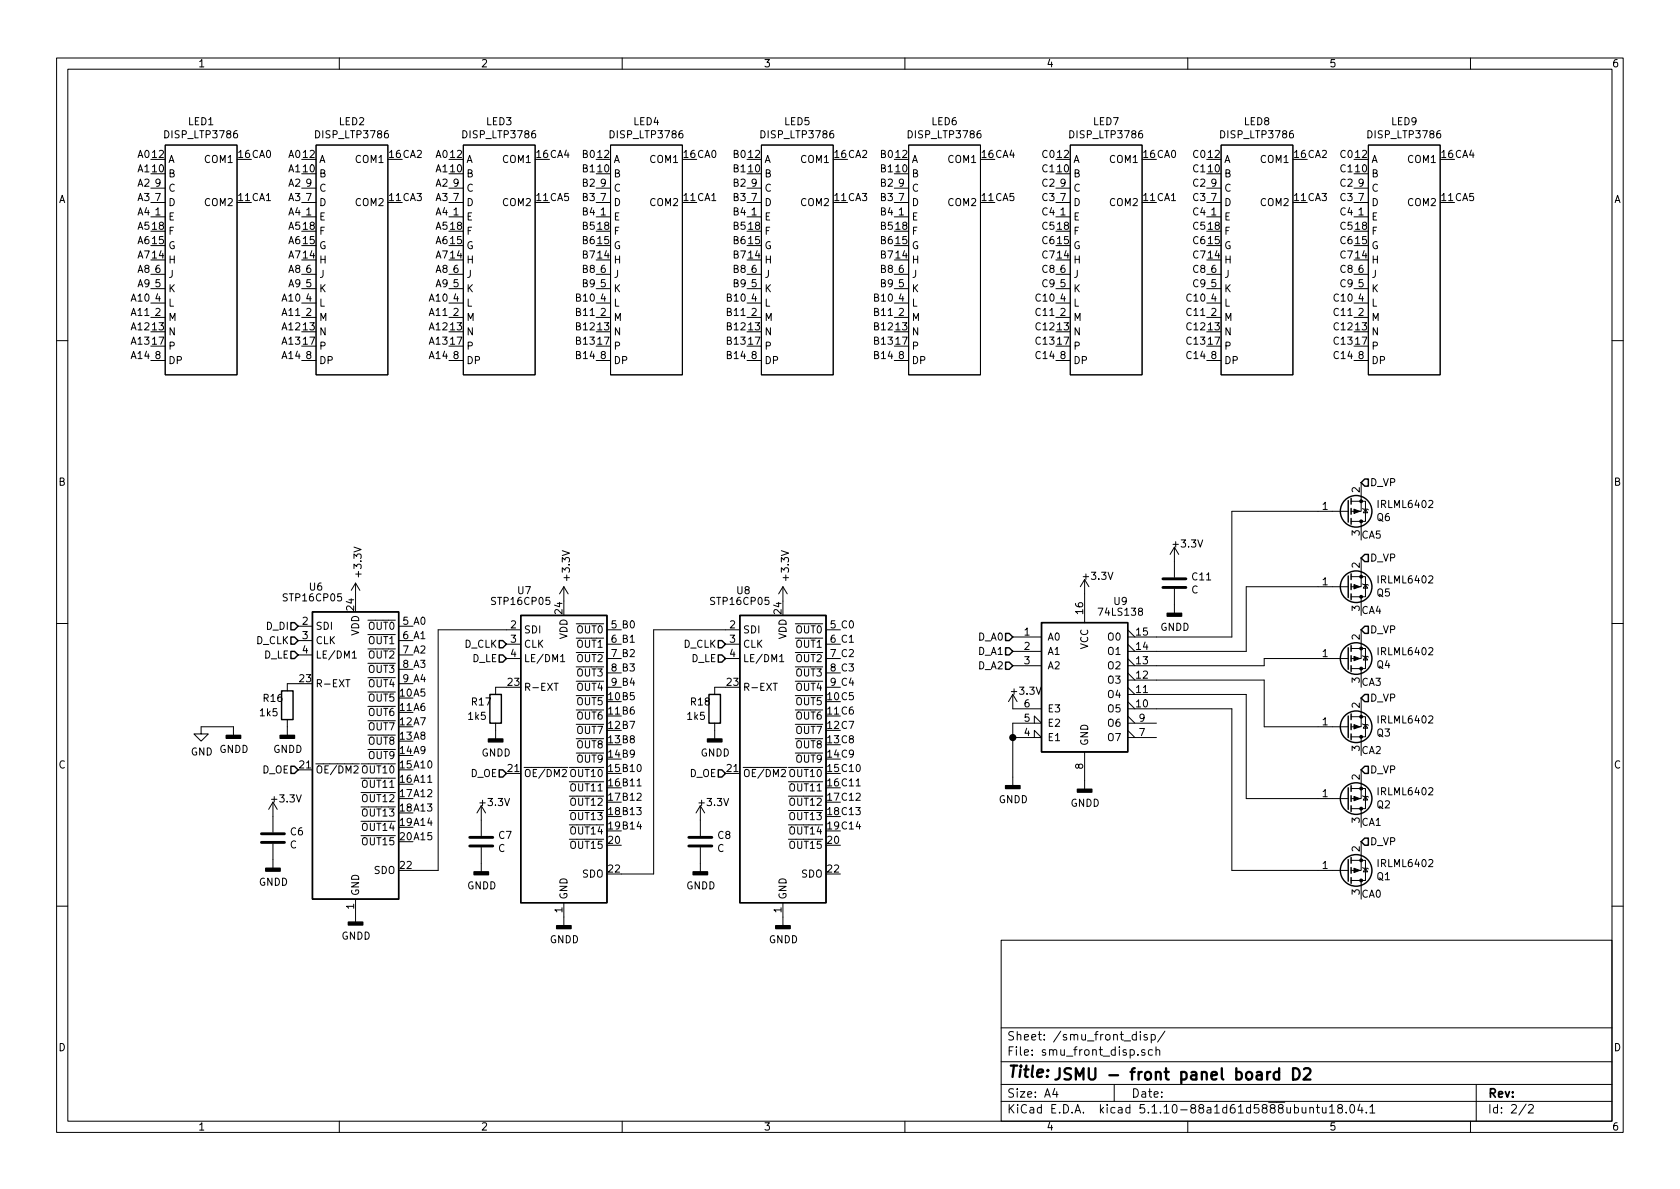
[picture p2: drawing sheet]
<svg xmlns="http://www.w3.org/2000/svg" width="297mm" height="210mm" viewBox="0 0 297 210" stroke-linecap="round" stroke-linejoin="round" font-family="sans-serif">
<defs><g id="words">
<text font-size="2.8" x="178" y="190.5">Title: JSMU - front panel board D2</text>
<g font-size="2.1">
<text x="178" y="184">Sheet: /smu_front_disp/</text>
<text x="178" y="186.7">File: smu_front_disp.sch</text>
<text x="178" y="196.9">KiCad E.D.A. kicad 5.1.10-88a1d61d5888ubuntu18.04.1</text>
<text x="178" y="194.1">Size: A4</text>
<text x="200" y="194.1">Date:</text>
<text x="263" y="194.1">Rev:</text>
<text x="263" y="196.9">Id: 2/2</text>
</g>
<g font-size="1.8">
<text x="35" y="11.9">1</text>
<text x="85" y="11.9">2</text>
<text x="135" y="11.9">3</text>
<text x="185" y="11.9">4</text>
<text x="235" y="11.9">5</text>
<text x="285" y="11.9">6</text>
<text x="33.3" y="22.1">LED1</text>
<text x="60" y="22.1">LED2</text>
<text x="86" y="22.1">LED3</text>
<text x="112" y="22.1">LED4</text>
<text x="138.7" y="22.1">LED5</text>
<text x="164.7" y="22.1">LED6</text>
<text x="193.3" y="22.1">LED7</text>
<text x="220" y="22.1">LED8</text>
<text x="246" y="22.1">LED9</text>
<text x="24.4" y="27.9">A0</text>
<text x="27" y="27.9">12</text>
<text x="29.4" y="24.5">DISP_LTP3786</text>
<text x="29.7" y="28.8">A</text>
<text x="36.3" y="28.8">COM1</text>
<text x="42.2" y="27.9">16CA0</text>
<text x="51.1" y="27.9">A0</text>
<text x="53.6" y="27.9">12</text>
<text x="56" y="24.5">DISP_LTP3786</text>
<text x="56.4" y="28.8">A</text>
<text x="63" y="28.8">COM1</text>
<text x="68.9" y="27.9">16CA2</text>
<text x="77.1" y="27.9">A0</text>
<text x="79.7" y="27.9">12</text>
<text x="82.1" y="24.5">DISP_LTP3786</text>
<text x="82.4" y="28.8">A</text>
<text x="89" y="28.8">COM1</text>
<text x="94.9" y="27.9">16CA4</text>
<text x="103.1" y="27.9">B0</text>
<text x="105.7" y="27.9">12</text>
<text x="108.1" y="24.5">DISP_LTP3786</text>
<text x="108.5" y="28.8">A</text>
<text x="115" y="28.8">COM1</text>
<text x="121" y="27.9">16CA0</text>
<text x="129.8" y="27.9">B0</text>
<text x="132.4" y="27.9">12</text>
<text x="134.8" y="24.5">DISP_LTP3786</text>
<text x="135.1" y="28.8">A</text>
<text x="141.7" y="28.8">COM1</text>
<text x="147.6" y="27.9">16CA2</text>
<text x="155.9" y="27.9">B0</text>
<text x="158.4" y="27.9">12</text>
<text x="160.8" y="24.5">DISP_LTP3786</text>
<text x="161.2" y="28.8">A</text>
<text x="167.7" y="28.8">COM1</text>
<text x="173.7" y="27.9">16CA4</text>
<text x="184.4" y="27.9">C0</text>
<text x="187" y="27.9">12</text>
<text x="189.4" y="24.5">DISP_LTP3786</text>
<text x="189.7" y="28.8">A</text>
<text x="196.3" y="28.8">COM1</text>
<text x="202.2" y="27.9">16CA0</text>
<text x="211.1" y="27.9">C0</text>
<text x="213.7" y="27.9">12</text>
<text x="216.1" y="24.5">DISP_LTP3786</text>
<text x="216.4" y="28.8">A</text>
<text x="223" y="28.8">COM1</text>
<text x="228.9" y="27.9">16CA2</text>
<text x="237.1" y="27.9">C0</text>
<text x="239.7" y="27.9">12</text>
<text x="242.1" y="24.5">DISP_LTP3786</text>
<text x="242.4" y="28.8">A</text>
<text x="249" y="28.8">COM1</text>
<text x="254.9" y="27.9">16CA4</text>
<text x="10.4" y="35.9">A</text>
<text x="24.4" y="30.5">A1</text>
<text x="24.4" y="33">A2</text>
<text x="24.4" y="35.6">A3</text>
<text x="27" y="30.5">10</text>
<text x="27.5" y="35.6">7</text>
<text x="27.5" y="33">9</text>
<text x="29.7" y="31.4">B</text>
<text x="29.7" y="33.9">C</text>
<text x="42.2" y="35.6">11CA1</text>
<text x="51.1" y="35.6">A3</text>
<text x="51.1" y="33">A2</text>
<text x="51.1" y="30.5">A1</text>
<text x="53.6" y="30.5">10</text>
<text x="54.1" y="35.6">7</text>
<text x="54.1" y="33">9</text>
<text x="56.4" y="31.4">B</text>
<text x="56.4" y="33.9">C</text>
<text x="68.9" y="35.6">11CA3</text>
<text x="77.1" y="35.6">A3</text>
<text x="77.1" y="33">A2</text>
<text x="77.1" y="30.5">A1</text>
<text x="79.7" y="30.5">10</text>
<text x="80.2" y="35.6">7</text>
<text x="80.2" y="33">9</text>
<text x="82.4" y="31.4">B</text>
<text x="82.4" y="33.9">C</text>
<text x="94.9" y="35.6">11CA5</text>
<text x="103.1" y="35.6">B3</text>
<text x="103.1" y="33">B2</text>
<text x="103.1" y="30.5">B1</text>
<text x="105.7" y="30.5">10</text>
<text x="106.2" y="35.6">7</text>
<text x="106.2" y="33">9</text>
<text x="108.5" y="31.4">B</text>
<text x="108.5" y="33.9">C</text>
<text x="121" y="35.6">11CA1</text>
<text x="129.8" y="35.6">B3</text>
<text x="129.8" y="33">B2</text>
<text x="129.8" y="30.5">B1</text>
<text x="132.4" y="30.5">10</text>
<text x="132.9" y="35.6">7</text>
<text x="132.9" y="33">9</text>
<text x="135.1" y="31.4">B</text>
<text x="135.1" y="33.9">C</text>
<text x="147.6" y="35.6">11CA3</text>
<text x="155.9" y="35.6">B3</text>
<text x="155.9" y="33">B2</text>
<text x="155.9" y="30.5">B1</text>
<text x="158.4" y="30.5">10</text>
<text x="158.9" y="35.6">7</text>
<text x="158.9" y="33">9</text>
<text x="161.2" y="31.4">B</text>
<text x="161.2" y="33.9">C</text>
<text x="173.7" y="35.6">11CA5</text>
<text x="184.4" y="35.6">C3</text>
<text x="184.4" y="33">C2</text>
<text x="184.4" y="30.5">C1</text>
<text x="187" y="30.5">10</text>
<text x="187.5" y="35.6">7</text>
<text x="187.5" y="33">9</text>
<text x="189.7" y="31.4">B</text>
<text x="189.7" y="33.9">C</text>
<text x="202.2" y="35.6">11CA1</text>
<text x="211.1" y="30.5">C1</text>
<text x="211.1" y="33">C2</text>
<text x="211.1" y="35.6">C3</text>
<text x="213.7" y="30.5">10</text>
<text x="214.1" y="35.6">7</text>
<text x="214.1" y="33">9</text>
<text x="216.4" y="31.4">B</text>
<text x="216.4" y="33.9">C</text>
<text x="228.9" y="35.6">11CA3</text>
<text x="237.1" y="35.6">C3</text>
<text x="237.1" y="33">C2</text>
<text x="237.1" y="30.5">C1</text>
<text x="239.7" y="30.5">10</text>
<text x="240.2" y="35.6">7</text>
<text x="240.2" y="33">9</text>
<text x="242.4" y="31.4">B</text>
<text x="242.4" y="33.9">C</text>
<text x="254.9" y="35.6">11CA5</text>
<text x="285.4" y="35.9">A</text>
<text x="24.4" y="40.6">A5</text>
<text x="24.4" y="38.1">A4</text>
<text x="27" y="40.6">18</text>
<text x="27.5" y="38.1">1</text>
<text x="29.7" y="39">E</text>
<text x="29.7" y="41.5">F</text>
<text x="29.7" y="36.4">D</text>
<text x="36.3" y="36.4">COM2</text>
<text x="51.1" y="40.6">A5</text>
<text x="51.1" y="38.1">A4</text>
<text x="53.6" y="40.6">18</text>
<text x="54.1" y="38.1">1</text>
<text x="56.4" y="39">E</text>
<text x="56.4" y="41.5">F</text>
<text x="56.4" y="36.4">D</text>
<text x="63" y="36.4">COM2</text>
<text x="77.1" y="40.6">A5</text>
<text x="77.1" y="38.1">A4</text>
<text x="79.7" y="40.6">18</text>
<text x="80.2" y="38.1">1</text>
<text x="82.4" y="39">E</text>
<text x="82.4" y="41.5">F</text>
<text x="82.4" y="36.4">D</text>
<text x="89" y="36.4">COM2</text>
<text x="103.1" y="40.6">B5</text>
<text x="103.1" y="38.1">B4</text>
<text x="105.7" y="40.6">18</text>
<text x="106.2" y="38.1">1</text>
<text x="108.5" y="39">E</text>
<text x="108.5" y="41.5">F</text>
<text x="108.5" y="36.4">D</text>
<text x="115" y="36.4">COM2</text>
<text x="129.8" y="40.6">B5</text>
<text x="129.8" y="38.1">B4</text>
<text x="132.4" y="40.6">18</text>
<text x="132.9" y="38.1">1</text>
<text x="135.1" y="39">E</text>
<text x="135.1" y="41.5">F</text>
<text x="135.1" y="36.4">D</text>
<text x="141.7" y="36.4">COM2</text>
<text x="155.9" y="38.1">B4</text>
<text x="155.9" y="40.6">B5</text>
<text x="158.4" y="40.6">18</text>
<text x="158.9" y="38.1">1</text>
<text x="161.2" y="39">E</text>
<text x="161.2" y="41.5">F</text>
<text x="161.2" y="36.4">D</text>
<text x="167.7" y="36.4">COM2</text>
<text x="184.4" y="40.6">C5</text>
<text x="184.4" y="38.1">C4</text>
<text x="187" y="40.6">18</text>
<text x="187.5" y="38.1">1</text>
<text x="189.7" y="39">E</text>
<text x="189.7" y="41.5">F</text>
<text x="189.7" y="36.4">D</text>
<text x="196.3" y="36.4">COM2</text>
<text x="211.1" y="40.6">C5</text>
<text x="211.1" y="38.1">C4</text>
<text x="213.7" y="40.6">18</text>
<text x="214.1" y="38.1">1</text>
<text x="216.4" y="39">E</text>
<text x="216.4" y="41.5">F</text>
<text x="216.4" y="36.4">D</text>
<text x="223" y="36.4">COM2</text>
<text x="237.1" y="40.6">C5</text>
<text x="237.1" y="38.1">C4</text>
<text x="239.7" y="40.6">18</text>
<text x="240.2" y="38.1">1</text>
<text x="242.4" y="39">E</text>
<text x="242.4" y="41.5">F</text>
<text x="242.4" y="36.4">D</text>
<text x="249" y="36.4">COM2</text>
<text x="24.4" y="45.7">A7</text>
<text x="24.4" y="43.2">A6</text>
<text x="27" y="45.7">14</text>
<text x="27" y="43.2">15</text>
<text x="29.7" y="46.6">H</text>
<text x="29.7" y="44.1">G</text>
<text x="51.1" y="45.7">A7</text>
<text x="51.1" y="43.2">A6</text>
<text x="53.6" y="45.7">14</text>
<text x="53.6" y="43.2">15</text>
<text x="56.4" y="46.6">H</text>
<text x="56.4" y="44.1">G</text>
<text x="77.1" y="45.7">A7</text>
<text x="77.1" y="43.2">A6</text>
<text x="79.7" y="45.7">14</text>
<text x="79.7" y="43.2">15</text>
<text x="82.4" y="46.6">H</text>
<text x="82.4" y="44.1">G</text>
<text x="103.1" y="45.7">B7</text>
<text x="103.1" y="43.2">B6</text>
<text x="105.7" y="45.7">14</text>
<text x="105.7" y="43.2">15</text>
<text x="108.5" y="46.6">H</text>
<text x="108.5" y="44.1">G</text>
<text x="129.8" y="45.7">B7</text>
<text x="129.8" y="43.2">B6</text>
<text x="132.4" y="45.7">14</text>
<text x="132.4" y="43.2">15</text>
<text x="135.1" y="46.6">H</text>
<text x="135.1" y="44.1">G</text>
<text x="155.9" y="45.7">B7</text>
<text x="155.9" y="43.2">B6</text>
<text x="158.4" y="45.7">14</text>
<text x="158.4" y="43.2">15</text>
<text x="161.2" y="46.6">H</text>
<text x="161.2" y="44.1">G</text>
<text x="184.4" y="45.7">C7</text>
<text x="184.4" y="43.2">C6</text>
<text x="187" y="45.7">14</text>
<text x="187" y="43.2">15</text>
<text x="189.7" y="46.6">H</text>
<text x="189.7" y="44.1">G</text>
<text x="211.1" y="43.2">C6</text>
<text x="211.1" y="45.7">C7</text>
<text x="213.7" y="45.7">14</text>
<text x="213.7" y="43.2">15</text>
<text x="216.4" y="46.6">H</text>
<text x="216.4" y="44.1">G</text>
<text x="237.1" y="45.7">C7</text>
<text x="237.1" y="43.2">C6</text>
<text x="239.7" y="45.7">14</text>
<text x="239.7" y="43.2">15</text>
<text x="242.4" y="46.6">H</text>
<text x="242.4" y="44.1">G</text>
<text x="23.4" y="53.3">A10</text>
<text x="24.4" y="50.8">A9</text>
<text x="24.4" y="48.3">A8</text>
<text x="27.5" y="53.3">4</text>
<text x="27.5" y="50.8">5</text>
<text x="27.5" y="48.3">6</text>
<text x="29.7" y="51.7">K</text>
<text x="29.7" y="49.1">J</text>
<text x="50.1" y="53.3">A10</text>
<text x="51.1" y="50.8">A9</text>
<text x="51.1" y="48.3">A8</text>
<text x="54.1" y="53.3">4</text>
<text x="54.1" y="50.8">5</text>
<text x="54.1" y="48.3">6</text>
<text x="56.4" y="51.7">K</text>
<text x="56.4" y="49.1">J</text>
<text x="76.1" y="53.3">A10</text>
<text x="77.1" y="48.3">A8</text>
<text x="77.1" y="50.8">A9</text>
<text x="80.2" y="53.3">4</text>
<text x="80.2" y="50.8">5</text>
<text x="80.2" y="48.3">6</text>
<text x="82.4" y="51.7">K</text>
<text x="82.4" y="49.1">J</text>
<text x="102.2" y="53.3">B10</text>
<text x="103.1" y="50.8">B9</text>
<text x="103.1" y="48.3">B8</text>
<text x="106.2" y="53.3">4</text>
<text x="106.2" y="50.8">5</text>
<text x="106.2" y="48.3">6</text>
<text x="108.5" y="51.7">K</text>
<text x="108.5" y="49.1">J</text>
<text x="128.8" y="53.3">B10</text>
<text x="129.8" y="50.8">B9</text>
<text x="129.8" y="48.3">B8</text>
<text x="132.9" y="53.3">4</text>
<text x="132.9" y="50.8">5</text>
<text x="132.9" y="48.3">6</text>
<text x="135.1" y="51.7">K</text>
<text x="135.1" y="49.1">J</text>
<text x="154.9" y="53.3">B10</text>
<text x="155.9" y="50.8">B9</text>
<text x="155.9" y="48.3">B8</text>
<text x="158.9" y="53.3">4</text>
<text x="158.9" y="50.8">5</text>
<text x="158.9" y="48.3">6</text>
<text x="161.2" y="51.7">K</text>
<text x="161.2" y="49.1">J</text>
<text x="183.4" y="53.3">C10</text>
<text x="184.4" y="48.3">C8</text>
<text x="184.4" y="50.8">C9</text>
<text x="187.5" y="53.3">4</text>
<text x="187.5" y="50.8">5</text>
<text x="187.5" y="48.3">6</text>
<text x="189.7" y="51.7">K</text>
<text x="189.7" y="49.1">J</text>
<text x="210.1" y="53.3">C10</text>
<text x="211.1" y="50.8">C9</text>
<text x="211.1" y="48.3">C8</text>
<text x="214.1" y="53.3">4</text>
<text x="214.1" y="50.8">5</text>
<text x="214.1" y="48.3">6</text>
<text x="216.4" y="51.7">K</text>
<text x="216.4" y="49.1">J</text>
<text x="236.1" y="53.3">C10</text>
<text x="237.1" y="50.8">C9</text>
<text x="237.1" y="48.3">C8</text>
<text x="240.2" y="53.3">4</text>
<text x="240.2" y="50.8">5</text>
<text x="240.2" y="48.3">6</text>
<text x="242.4" y="51.7">K</text>
<text x="242.4" y="49.1">J</text>
<text x="23.4" y="55.9">A11</text>
<text x="23.4" y="58.4">A12</text>
<text x="27" y="58.4">13</text>
<text x="27.5" y="55.9">2</text>
<text x="29.7" y="59.3">N</text>
<text x="29.7" y="56.8">M</text>
<text x="29.7" y="54.2">L</text>
<text x="50.1" y="58.4">A12</text>
<text x="50.1" y="55.9">A11</text>
<text x="53.6" y="58.4">13</text>
<text x="54.1" y="55.9">2</text>
<text x="56.4" y="59.3">N</text>
<text x="56.4" y="56.8">M</text>
<text x="56.4" y="54.2">L</text>
<text x="76.1" y="58.4">A12</text>
<text x="76.1" y="55.9">A11</text>
<text x="79.7" y="58.4">13</text>
<text x="80.2" y="55.9">2</text>
<text x="82.4" y="59.3">N</text>
<text x="82.4" y="56.8">M</text>
<text x="82.4" y="54.2">L</text>
<text x="102.2" y="58.4">B12</text>
<text x="102.2" y="55.9">B11</text>
<text x="105.7" y="58.4">13</text>
<text x="106.2" y="55.9">2</text>
<text x="108.5" y="59.3">N</text>
<text x="108.5" y="56.8">M</text>
<text x="108.5" y="54.2">L</text>
<text x="128.8" y="58.4">B12</text>
<text x="128.8" y="55.9">B11</text>
<text x="132.4" y="58.4">13</text>
<text x="132.9" y="55.9">2</text>
<text x="135.1" y="59.3">N</text>
<text x="135.1" y="56.8">M</text>
<text x="135.1" y="54.2">L</text>
<text x="154.9" y="58.4">B12</text>
<text x="154.9" y="55.9">B11</text>
<text x="158.4" y="58.4">13</text>
<text x="158.9" y="55.9">2</text>
<text x="161.2" y="59.3">N</text>
<text x="161.2" y="56.8">M</text>
<text x="161.2" y="54.2">L</text>
<text x="183.4" y="55.9">C11</text>
<text x="183.4" y="58.4">C12</text>
<text x="187" y="58.4">13</text>
<text x="187.5" y="55.9">2</text>
<text x="189.7" y="59.3">N</text>
<text x="189.7" y="56.8">M</text>
<text x="189.7" y="54.2">L</text>
<text x="210.1" y="58.4">C12</text>
<text x="210.1" y="55.9">C11</text>
<text x="213.7" y="58.4">13</text>
<text x="214.1" y="55.9">2</text>
<text x="216.4" y="59.3">N</text>
<text x="216.4" y="56.8">M</text>
<text x="216.4" y="54.2">L</text>
<text x="236.1" y="58.4">C12</text>
<text x="236.1" y="55.9">C11</text>
<text x="239.7" y="58.4">13</text>
<text x="240.2" y="55.9">2</text>
<text x="242.4" y="59.3">N</text>
<text x="242.4" y="56.8">M</text>
<text x="242.4" y="54.2">L</text>
<text x="23.4" y="63.5">A14</text>
<text x="23.4" y="61">A13</text>
<text x="27" y="61">17</text>
<text x="27.5" y="63.5">8</text>
<text x="29.7" y="61.8">P</text>
<text x="29.7" y="64.4">DP</text>
<text x="50.1" y="63.5">A14</text>
<text x="50.1" y="61">A13</text>
<text x="53.6" y="61">17</text>
<text x="54.1" y="63.5">8</text>
<text x="56.4" y="61.8">P</text>
<text x="56.4" y="64.4">DP</text>
<text x="76.1" y="63.5">A14</text>
<text x="76.1" y="61">A13</text>
<text x="79.7" y="61">17</text>
<text x="80.2" y="63.5">8</text>
<text x="82.4" y="61.8">P</text>
<text x="82.4" y="64.4">DP</text>
<text x="102.2" y="63.5">B14</text>
<text x="102.2" y="61">B13</text>
<text x="105.7" y="61">17</text>
<text x="106.2" y="63.5">8</text>
<text x="108.5" y="61.8">P</text>
<text x="108.5" y="64.4">DP</text>
<text x="128.8" y="63.5">B14</text>
<text x="128.8" y="61">B13</text>
<text x="132.4" y="61">17</text>
<text x="132.9" y="63.5">8</text>
<text x="135.1" y="61.8">P</text>
<text x="135.1" y="64.4">DP</text>
<text x="154.9" y="61">B13</text>
<text x="154.9" y="63.5">B14</text>
<text x="158.4" y="61">17</text>
<text x="158.9" y="63.5">8</text>
<text x="161.2" y="61.8">P</text>
<text x="161.2" y="64.4">DP</text>
<text x="183.4" y="61">C13</text>
<text x="183.4" y="63.5">C14</text>
<text x="187" y="61">17</text>
<text x="187.5" y="63.5">8</text>
<text x="189.7" y="61.8">P</text>
<text x="189.7" y="64.4">DP</text>
<text x="210.1" y="63.5">C14</text>
<text x="210.1" y="61">C13</text>
<text x="213.7" y="61">17</text>
<text x="214.1" y="63.5">8</text>
<text x="216.4" y="61.8">P</text>
<text x="216.4" y="64.4">DP</text>
<text x="236.1" y="63.5">C14</text>
<text x="236.1" y="61">C13</text>
<text x="239.7" y="61">17</text>
<text x="240.2" y="63.5">8</text>
<text x="242.4" y="61.8">P</text>
<text x="242.4" y="64.4">DP</text>
<text x="10.4" y="85.9">B</text>
<text x="240.4" y="87.1" transform="rotate(-90 240.4 87.1)">2</text>
<text x="242.2" y="86">D_VP</text>
<text x="243.8" y="89.8">IRLML6402</text>
<text x="285.4" y="85.9">B</text>
<text x="233.8" y="90.2">1</text>
<text x="240.4" y="94.7" transform="rotate(-90 240.4 94.7)">3</text>
<text x="240.7" y="95.2">CA5</text>
<text x="243.5" y="92.1">Q6</text>
<text x="63.9" y="101.8" transform="rotate(-90 63.9 101.8)">+3.3V</text>
<text x="207.6" y="96.8">+3.3V</text>
<text x="240.4" y="100.4" transform="rotate(-90 240.4 100.4)">2</text>
<text x="242.2" y="99.3">D_VP</text>
<text x="50.3" y="106.3">STP16CP05</text>
<text x="54.8" y="104.4">U6</text>
<text x="62.6" y="107.9" transform="rotate(-90 62.6 107.9)">24</text>
<text x="87.2" y="107">STP16CP05</text>
<text x="91.6" y="105.1">U7</text>
<text x="100.8" y="102.5" transform="rotate(-90 100.8 102.5)">+3.3V</text>
<text x="125.9" y="107">STP16CP05</text>
<text x="130.3" y="105.1">U8</text>
<text x="139.5" y="102.5" transform="rotate(-90 139.5 102.5)">+3.3V</text>
<text x="191.7" y="102.5">+3.3V</text>
<text x="197" y="107">U9</text>
<text x="210.6" y="104.9">C</text>
<text x="210.8" y="102.6">C11</text>
<text x="233.8" y="103.5">1</text>
<text x="243.5" y="105.5">Q5</text>
<text x="243.8" y="103.2">IRLML6402</text>
<text x="45.3" y="113.9">D_CLK</text>
<text x="47.1" y="111.4">D_DI</text>
<text x="53.5" y="110.5">2</text>
<text x="53.5" y="113">3</text>
<text x="55.8" y="111.4">SDI</text>
<text x="55.8" y="113.9">CLK</text>
<text x="63.5" y="112.4" transform="rotate(-90 63.5 112.4)">VDD</text>
<text x="65.3" y="111.4">OUT0</text>
<text x="65.3" y="113.9">OUT1</text>
<text x="71.3" y="110.5">5 A0</text>
<text x="71.3" y="113">6 A1</text>
<text x="90.3" y="111.1">2</text>
<text x="90.3" y="113.7">3</text>
<text x="92.6" y="112">SDI</text>
<text x="99.4" y="108.5" transform="rotate(-90 99.4 108.5)">24</text>
<text x="100.3" y="113.1" transform="rotate(-90 100.3 113.1)">VDD</text>
<text x="102.1" y="112">OUT0</text>
<text x="108.1" y="111.1">5 B0</text>
<text x="108.1" y="113.7">6 B1</text>
<text x="129.1" y="111.1">2</text>
<text x="129.1" y="113.7">3</text>
<text x="131.3" y="112">SDI</text>
<text x="138.2" y="108.5" transform="rotate(-90 138.2 108.5)">24</text>
<text x="139.1" y="113.1" transform="rotate(-90 139.1 113.1)">VDD</text>
<text x="140.8" y="112">OUT0</text>
<text x="146.8" y="111.1">5 C0</text>
<text x="146.8" y="113.7">6 C1</text>
<text x="173" y="113.3">D_A0</text>
<text x="181.1" y="112.4">1</text>
<text x="185.2" y="113.3">A0</text>
<text x="191.5" y="108.5" transform="rotate(-90 191.5 108.5)">16</text>
<text x="194.5" y="108.9">74LS138</text>
<text x="196" y="113.3">O0</text>
<text x="201" y="112.4">15</text>
<text x="205.2" y="111.6">GNDD</text>
<text x="240.4" y="113.1" transform="rotate(-90 240.4 113.1)">2</text>
<text x="240.4" y="108" transform="rotate(-90 240.4 108)">3</text>
<text x="240.7" y="108.6">CA4</text>
<text x="242.2" y="112">D_VP</text>
<text x="46.7" y="116.5">D_LE</text>
<text x="53.5" y="115.6">4</text>
<text x="55.8" y="116.5">LE/DM1</text>
<text x="65.3" y="116.5">OUT2</text>
<text x="65.3" y="119">OUT3</text>
<text x="71.3" y="115.6">7 A2</text>
<text x="71.3" y="118.1">8 A3</text>
<text x="82.1" y="114.5">D_CLK</text>
<text x="83.5" y="117.1">D_LE</text>
<text x="90.3" y="116.2">4</text>
<text x="92.6" y="114.5">CLK</text>
<text x="92.6" y="117.1">LE/DM1</text>
<text x="102.1" y="114.5">OUT1</text>
<text x="102.1" y="117.1">OUT2</text>
<text x="102.1" y="119.6">OUT3</text>
<text x="108.1" y="116.2">7 B2</text>
<text x="108.1" y="118.7">8 B3</text>
<text x="120.9" y="114.5">D_CLK</text>
<text x="122.2" y="117.1">D_LE</text>
<text x="129.1" y="116.2">4</text>
<text x="131.3" y="114.5">CLK</text>
<text x="131.3" y="117.1">LE/DM1</text>
<text x="140.8" y="114.5">OUT1</text>
<text x="140.8" y="117.1">OUT2</text>
<text x="140.8" y="119.6">OUT3</text>
<text x="146.8" y="116.2">7 C2</text>
<text x="146.8" y="118.7">8 C3</text>
<text x="173" y="115.8">D_A1</text>
<text x="173" y="118.4">D_A2</text>
<text x="181.1" y="114.9">2</text>
<text x="181.1" y="117.5">3</text>
<text x="185.2" y="115.8">A1</text>
<text x="185.2" y="118.4">A2</text>
<text x="192.4" y="114.9" transform="rotate(-90 192.4 114.9)">VCC</text>
<text x="196" y="118.4">O2</text>
<text x="196" y="115.8">O1</text>
<text x="201" y="117.5">13</text>
<text x="201" y="114.9">14</text>
<text x="233.8" y="116.2">1</text>
<text x="243.5" y="118.2">Q4</text>
<text x="243.8" y="115.9">IRLML6402</text>
<text x="46.6" y="124.1">R16</text>
<text x="53" y="120.6">23</text>
<text x="55.8" y="121.5">R-EXT</text>
<text x="65.3" y="124.1">OUT5</text>
<text x="65.3" y="121.5">OUT4</text>
<text x="70.8" y="123.2">10A5</text>
<text x="70.8" y="125.7">11A6</text>
<text x="71.3" y="120.6">9 A4</text>
<text x="83.5" y="124.8">R17</text>
<text x="89.8" y="121.3">23</text>
<text x="92.6" y="122.2">R-EXT</text>
<text x="102.1" y="124.7">OUT5</text>
<text x="102.1" y="122.2">OUT4</text>
<text x="107.6" y="123.8">10B5</text>
<text x="108.1" y="121.3">9 B4</text>
<text x="122.2" y="124.8">R18</text>
<text x="128.6" y="121.3">23</text>
<text x="131.3" y="122.2">R-EXT</text>
<text x="140.8" y="124.7">OUT5</text>
<text x="140.8" y="122.2">OUT4</text>
<text x="146.4" y="123.8">10C5</text>
<text x="146.8" y="121.3">9 C4</text>
<text x="179" y="122.9">+3.3V</text>
<text x="181.1" y="125.1">6</text>
<text x="185.2" y="126">E3</text>
<text x="196" y="126">O5</text>
<text x="196" y="123.4">O4</text>
<text x="196" y="120.9">O3</text>
<text x="201" y="125.1">10</text>
<text x="201" y="122.5">11</text>
<text x="201" y="120">12</text>
<text x="240.4" y="125.2" transform="rotate(-90 240.4 125.2)">2</text>
<text x="240.4" y="120.7" transform="rotate(-90 240.4 120.7)">3</text>
<text x="240.7" y="121.3">CA3</text>
<text x="242.2" y="124.1">D_VP</text>
<text x="46.1" y="126.7">1k5</text>
<text x="65.3" y="126.6">OUT6</text>
<text x="65.3" y="129.2">OUT7</text>
<text x="65.3" y="131.7">OUT8</text>
<text x="70.8" y="128.3">12A7</text>
<text x="70.8" y="130.8">13A8</text>
<text x="82.9" y="127.3">1k5</text>
<text x="102.1" y="127.2">OUT6</text>
<text x="102.1" y="129.8">OUT7</text>
<text x="107.6" y="126.4">11B6</text>
<text x="107.6" y="128.9">12B7</text>
<text x="107.6" y="131.4">13B8</text>
<text x="121.6" y="127.3">1k5</text>
<text x="140.8" y="127.2">OUT6</text>
<text x="140.8" y="129.8">OUT7</text>
<text x="146.4" y="126.4">11C6</text>
<text x="146.4" y="128.9">12C7</text>
<text x="146.4" y="131.4">13C8</text>
<text x="181.1" y="130.2">4</text>
<text x="181.1" y="127.6">5</text>
<text x="185.2" y="131.1">E1</text>
<text x="185.2" y="128.5">E2</text>
<text x="192.4" y="131.9" transform="rotate(-90 192.4 131.9)">GND</text>
<text x="196" y="131.1">O7</text>
<text x="196" y="128.5">O6</text>
<text x="201.4" y="130.2">7</text>
<text x="201.4" y="127.6">9</text>
<text x="233.8" y="128.3">1</text>
<text x="243.5" y="130.2">Q3</text>
<text x="243.8" y="127.9">IRLML6402</text>
<text x="10.4" y="135.9">C</text>
<text x="33.7" y="133.6">GND</text>
<text x="38.8" y="133.1">GNDD</text>
<text x="46.4" y="136.8">D_OE</text>
<text x="48.3" y="133.1">GNDD</text>
<text x="53" y="135.9">21</text>
<text x="55.8" y="136.8">OE/DM2</text>
<text x="64.3" y="136.8">OUT10</text>
<text x="65.3" y="134.2">OUT9</text>
<text x="70.8" y="133.3">14A9</text>
<text x="70.8" y="135.9">15A10</text>
<text x="83.2" y="137.4">D_OE</text>
<text x="85.1" y="133.8">GNDD</text>
<text x="89.8" y="136.5">21</text>
<text x="92.6" y="137.4">OE/DM2</text>
<text x="101.1" y="137.4">OUT10</text>
<text x="102.1" y="132.3">OUT8</text>
<text x="102.1" y="134.9">OUT9</text>
<text x="107.6" y="134">14B9</text>
<text x="107.6" y="136.5">15B10</text>
<text x="121.9" y="137.4">D_OE</text>
<text x="123.9" y="133.8">GNDD</text>
<text x="128.6" y="136.5">21</text>
<text x="131.3" y="137.4">OE/DM2</text>
<text x="139.9" y="137.4">OUT10</text>
<text x="140.8" y="132.3">OUT8</text>
<text x="140.8" y="134.9">OUT9</text>
<text x="146.4" y="134">14C9</text>
<text x="146.4" y="136.5">15C10</text>
<text x="191.5" y="136" transform="rotate(-90 191.5 136)">8</text>
<text x="240.4" y="137.9" transform="rotate(-90 240.4 137.9)">2</text>
<text x="240.4" y="132.8" transform="rotate(-90 240.4 132.8)">3</text>
<text x="240.7" y="133.3">CA2</text>
<text x="242.2" y="136.8">D_VP</text>
<text x="285.4" y="135.9">C</text>
<text x="48.2" y="141.9">+3.3V</text>
<text x="64.3" y="139.3">OUT11</text>
<text x="64.3" y="141.9">OUT12</text>
<text x="70.8" y="138.4">16A11</text>
<text x="70.8" y="141">17A12</text>
<text x="70.8" y="143.5">18A13</text>
<text x="85" y="142.5">+3.3V</text>
<text x="101.1" y="139.9">OUT11</text>
<text x="101.1" y="142.5">OUT12</text>
<text x="107.6" y="139.1">16B11</text>
<text x="107.6" y="141.6">17B12</text>
<text x="123.8" y="142.5">+3.3V</text>
<text x="139.9" y="139.9">OUT11</text>
<text x="139.9" y="142.5">OUT12</text>
<text x="146.4" y="139.1">16C11</text>
<text x="146.4" y="141.6">17C12</text>
<text x="176.6" y="142">GNDD</text>
<text x="189.3" y="142.7">GNDD</text>
<text x="233.8" y="141">1</text>
<text x="243.5" y="142.9">Q2</text>
<text x="243.8" y="140.6">IRLML6402</text>
<text x="51.4" y="147.7">C6</text>
<text x="64.3" y="144.4">OUT13</text>
<text x="64.3" y="146.9">OUT14</text>
<text x="64.3" y="149.5">OUT15</text>
<text x="70.8" y="146">19A14</text>
<text x="70.8" y="148.6">20A15</text>
<text x="88.2" y="148.4">C7</text>
<text x="101.1" y="145">OUT13</text>
<text x="101.1" y="147.6">OUT14</text>
<text x="107.6" y="144.1">18B13</text>
<text x="107.6" y="146.7">19B14</text>
<text x="107.6" y="149.2">20</text>
<text x="126.9" y="148.4">C8</text>
<text x="139.9" y="145">OUT13</text>
<text x="139.9" y="147.6">OUT14</text>
<text x="146.4" y="144.1">18C13</text>
<text x="146.4" y="146.7">19C14</text>
<text x="146.4" y="149.2">20</text>
<text x="240.4" y="145.5" transform="rotate(-90 240.4 145.5)">3</text>
<text x="240.7" y="146">CA1</text>
<text x="242.2" y="149.5">D_VP</text>
<text x="51.3" y="150">C</text>
<text x="66.1" y="154.6">SDO</text>
<text x="70.8" y="153.7">22</text>
<text x="88.1" y="150.7">C</text>
<text x="101.1" y="150.1">OUT15</text>
<text x="103" y="155.2">SDO</text>
<text x="107.6" y="154.3">22</text>
<text x="126.8" y="150.7">C</text>
<text x="139.9" y="150.1">OUT15</text>
<text x="141.7" y="155.2">SDO</text>
<text x="146.4" y="154.3">22</text>
<text x="233.8" y="153.7">1</text>
<text x="240.4" y="150.6" transform="rotate(-90 240.4 150.6)">2</text>
<text x="243.5" y="155.6">Q1</text>
<text x="243.8" y="153.3">IRLML6402</text>
<text x="45.8" y="156.6">GNDD</text>
<text x="62.6" y="160.8" transform="rotate(-90 62.6 160.8)">1</text>
<text x="63.5" y="158.5" transform="rotate(-90 63.5 158.5)">GND</text>
<text x="82.6" y="157.3">GNDD</text>
<text x="99.4" y="161.4" transform="rotate(-90 99.4 161.4)">1</text>
<text x="100.3" y="159.1" transform="rotate(-90 100.3 159.1)">GND</text>
<text x="121.3" y="157.3">GNDD</text>
<text x="138.2" y="161.4" transform="rotate(-90 138.2 161.4)">1</text>
<text x="139.1" y="159.1" transform="rotate(-90 139.1 159.1)">GND</text>
<text x="240.4" y="158.2" transform="rotate(-90 240.4 158.2)">3</text>
<text x="240.7" y="158.7">CA0</text>
<text x="60.4" y="166.2">GNDD</text>
<text x="97.2" y="166.8">GNDD</text>
<text x="135.9" y="166.8">GNDD</text>
<text x="10.4" y="185.9">D</text>
<text x="285.4" y="185.9">D</text>
<text x="35" y="199.9">1</text>
<text x="85" y="199.9">2</text>
<text x="135" y="199.9">3</text>
<text x="185" y="199.9">4</text>
<text x="235" y="199.9">5</text>
<text x="285" y="199.9">6</text>
</g>
</g></defs>
<g fill="none" stroke="#000" stroke-width=".18">
<path d="M10 10.3h277v189.9h-277zM12 12.2h273v186.1h-273zM60 10.3v1.9M110 10.3v1.9M160 10.3v1.9M210 10.3v1.9M260 10.3v1.9M26.7 38.3h2.5M26.7 35.8h2.5M26.7 33.3h2.5M29.2 25.6h12.7v40.7h-12.7zM53.3 38.3h2.6"/>
<path d="M53.3 35.8h2.6M53.3 33.3h2.6M55.9 25.6h12.7v40.7h-12.7zM79.4 38.3h2.5M79.4 35.8h2.5M79.4 33.3h2.5M81.9 25.6h12.7v40.7h-12.7zM105.4 38.3h2.5M105.4 35.8h2.5M105.4 33.3h2.5M107.9 25.6h12.7v40.7h-12.7zM132.1 38.3h2.5"/>
<path d="M132.1 35.8h2.5M132.1 33.3h2.5M134.6 25.6h12.7v40.7h-12.7zM158.1 38.3h2.6M158.1 35.8h2.6M158.1 33.3h2.6M160.7 25.6h12.7v40.7h-12.7zM186.7 38.3h2.5M186.7 35.8h2.5M186.7 33.3h2.5M189.2 25.6h12.7v40.7h-12.7zM213.4 38.3h2.5"/>
<path d="M213.4 35.8h2.5M213.4 33.3h2.5M215.9 25.6h12.7v40.7h-12.7zM239.4 38.3h2.5M239.4 35.8h2.5M239.4 33.3h2.5M241.9 25.6h12.7v40.7h-12.7zM26.7 56.1h2.5M26.7 53.6h2.5M26.7 51h2.5M26.7 48.5h2.5M53.3 56.1h2.6"/>
<path d="M53.3 53.6h2.6M53.3 51h2.6M53.3 48.5h2.6M79.4 56.1h2.5M79.4 53.6h2.5M79.4 51h2.5M79.4 48.5h2.5M105.4 56.1h2.5M105.4 53.6h2.5M105.4 51h2.5M105.4 48.5h2.5M132.1 56.1h2.5"/>
<path d="M132.1 53.6h2.5M132.1 51h2.5M132.1 48.5h2.5M158.1 56.1h2.6M158.1 53.6h2.6M158.1 51h2.6M158.1 48.5h2.6M186.7 56.1h2.5M186.7 53.6h2.5M186.7 51h2.5M186.7 48.5h2.5M213.4 56.1h2.5"/>
<path d="M213.4 53.6h2.5M213.4 51h2.5M213.4 48.5h2.5M239.4 56.1h2.5M239.4 53.6h2.5M239.4 51h2.5M239.4 48.5h2.5M10 60.2h2M26.7 63.7h2.5M53.3 63.7h2.6M79.4 63.7h2.5M105.4 63.7h2.5"/>
<path d="M132.1 63.7h2.5M158.1 63.7h2.6M186.7 63.7h2.5M213.4 63.7h2.5M239.4 63.7h2.5M285 60.2h2M207.6 96.8l-.7 1.2M207.6 96.8v5.3M207.6 96.8l.8 1.2M238.4 90.4h-20.6v22.2h-18.4M238.9 88.6h2.5v3.6h-2.5M240.7 98.7v5.1h-1.8"/>
<path d="M240.7 85.3v5.1h-1.8M240.7 92.2v3.3M240.9 89.9l.1 .1h.8l.1 .2M241.4 90l.4 .7h-.8zM10 110.3h2M52.7 110.7h2.5M52.7 113.3h2.5M52.7 115.8h2.5M62.3 115.5l.4-.4v1.3M62.3 116.4h.7M62.9 103.1v2.6M62.9 103.1l-.8 1.3"/>
<path d="M62.9 103.1l.7 1.3M70.5 110.7h2.5M70.5 113.3h2.5M70.5 115.8h2.5M70.5 118.4h2.5M89.5 113.9h2.6M89.5 116.5h2.6M92.1 111.4h-14.6v42.5h-4.5M99.1 116.1l.4-.4v1.3M99.1 117h.7M99.7 103.8v2.5M99.7 103.8l-.8 1.2"/>
<path d="M99.7 103.8l.8 1.2M107.3 111.4h2.6M107.3 113.9h2.6M107.3 116.5h2.6M107.3 119h2.6M128.3 113.9h2.5M128.3 116.5h2.5M130.8 111.4h-15.2v43.2h-5.7M137.8 116.1l.4-.4v1.3M137.8 117h.8M138.4 103.8v2.5M138.4 103.8l-.7 1.2"/>
<path d="M138.4 103.8l.8 1.2M146 111.4h2.6M146 113.9h2.6M146 116.5h2.6M146 119h2.6M179.1 112.6h5M179.1 117.7h5M179.1 115.2h5M191.8 102.5v7.6M191.8 102.5l-.8 1.3M191.8 102.5l.7 1.3M199.4 119l1.3 1.3"/>
<path d="M199.4 116.5l1.3 1.2M199.4 113.9l1.3 1.3M199.4 111.4l1.3 1.2M207.6 104.1v4.4M238.4 116.5h-14.9v1.2h-24.1M238.4 103.8h-18.1v11.4h-20.9M238.9 114.7h2.5v3.5h-2.5M238.9 102h2.5v3.5h-2.5M240.7 111.4v5.1h-1.8M240.7 105.5v3.3M240.7 118.2v3.3M240.9 115.9l.1 .2h.8l.1 .1"/>
<path d="M240.9 103.2l.1 .2h.8l.1 .1M241.4 116.1l.4 .6h-.8zM241.4 103.4l.4 .6h-.8zM285 110.3h2M35.6 129.8h-1.3l1.3 1.3 1.2-1.3h-1.2v-1.3h5.7v1.5M50.8 127.2v2.8M52.7 120.9h-1.9v1.3M61.1 120.2h.8M62.4 135.1h1.2M62.6 135.6l.5-.2 .2 .4-.8 .9h.8M70.5 120.9h2.5M87.6 127.9v2.8"/>
<path d="M89.5 121.5h-1.9v1.3M98 120.8h.7M99.2 135.7h1.2M99.4 136.2l.5-.1 .3 .3-.8 .9h.8M107.3 121.5h2.6M112.6 139h.8M126.4 127.9v2.8M128.3 121.5h-1.9v1.3M136.7 120.8h.7M137.9 135.7h1.2M138.2 136.2l.4-.1 .3 .3-.8 .9h.8M146 121.5h2.6"/>
<path d="M179.1 130.4h5l-1.2-1.2v1.2M179.1 122.8v2.5h5M179.1 122.8l-.8 1.3M179.1 122.8l.7 1.3M182.9 127.9v-1.3l1.2 1.3h-5v11M191.8 133v6.6M199.4 125.3h18.4v28.6h20.6M199.4 124.1l1.3 1.2M199.4 122.8h20.9v18.4h18.1M199.4 121.5l1.3 1.3M199.4 120.3h24.1v8.2h14.9M199.4 130.4h5.1"/>
<path d="M199.4 127.9h5.1M199.4 129.2l1.3 1.2M199.4 126.6l1.3 1.3M238.9 139.4h2.5v3.6h-2.5M238.9 126.7h2.5v3.6h-2.5M240.7 136.1v5.1h-1.8M240.7 123.4v5.1h-1.8M240.7 130.3v3.3M240.9 128l.1 .1h.8l.1 .2M241.4 128.1l.4 .7h-.8zM48.3 141.9l-.8 1.2M48.3 141.9v5.3"/>
<path d="M48.3 149.2v4.3M48.3 141.9l.7 1.2M62.9 159v4.1M85.1 142.5v5.3M85.1 149.9v4.3M85.1 142.5l-.8 1.3M85.1 142.5l.8 1.3M99.7 159.6v4.1M123.8 142.5v5.3M123.8 149.9v4.3M123.8 142.5l-.7 1.3M123.8 142.5l.8 1.3"/>
<path d="M138.4 159.6v4.1M238.9 152.1h2.5v3.6h-2.5M240.7 148.8v5.1h-1.8M240.7 143v3.3M240.7 155.7v3.3M240.9 153.4l.1 .1h.8l.1 .2M240.9 140.7l.1 .1h.8l.1 .2M241.4 153.5l.4 .7h-.8zM241.4 140.8l.4 .7h-.8zM10 160.2h2M177 166.3h108v32h-108zM285 160.2h2"/>
<path d="M60 198.3v1.9M110 198.3v1.9M160 198.3v1.9M177 194.8h108M177 191.8h108M177 187.8h108M177 181.8h108M186.5 192.5l-.4 1h1M186.8 193v1M197 191.8v3M200.9 183l-.4-.1-.3 .3 .1 .6 .2 .1 .4-.1M200.9 182.4v1.5"/>
<path d="M201.2 186.5v.1M201.6 182.4v.2M201.6 182.9v1M202.4 185.7a.37 .37 0 0 0-.6 .1l.1 .2 .5 .2 .1 .1-.2 .3-.5-.1M202.8 183l-.3-.1-.2 .2v.3l.5 .1v.3h-.5M203.6 183l.4-.1 .3 .3-.1 .6-.2 .1-.4-.1M203.6 182.9v1.5M203.8 185.7l-.5-.1-.3 .3 .2 .6h.6M204.4 185.7h.1a.37 .37 0 0 1 .6 .1v.8M204.4 185.1v1.5M206 182.3l-1.3 2M210 198.3v1.9"/>
<path d="M231.6 196l.2-.2 .4 .1v.9M231.6 195.8v1M232.7 195.8h.6M232.9 195.3v1.3l.4 .2M233.8 195.8l.1 .9 .3 .1 .2-.1M234.4 195.8v1M235.1 195.8l.4-.5v1.5M235.1 196.8h.8M236.8 196l-.2-.2v-.3a.48 .48 0 0 1 .6-.1l.2 .2-.2 .3-.5 .1-.2 .3 .1 .4 .2 .1h.3l.3-.3v-.2l-.3-.3M238 196.7v.1M238.8 195.5l.3-.2a.94 .94 0 0 1 0 1.5 .82 .82 0 0 1-.3-1.3zM240.4 195.2l-.3 1.1h.9"/>
<path d="M240.8 195.8v1M241.6 196.7v.1M242.2 195.8l.4-.5v1.5M242.2 196.8h.9M260 198.3v1.9M261 191.8v6.5M269.8 195.2l-1.2 2M270.3 195.5l.2-.2h.3l.3 .5-.9 1h.9"/>
</g>
<g fill="none" stroke="#000" stroke-width=".25">
<path d="M238.4 88.5v3.8M238.9 88.1v1M238.9 89.9v1M238.9 91.7v1M241.3 84.7h.6v1.3h-.6l-.6-.7zM241.3 98h.6v1.3h-.6l-.6-.6zM51.4 112.6h.7l.6 .7-.6 .6h-.7zM51.4 115.2h.7l.6 .6-.6 .7h-.7zM51.4 110.1h.7l.6 .6-.6 .7h-.7zM55.2 108.2h15.3v50.8h-15.3zM88.3 113.3h.6l.6 .6-.6 .6h-.6zM88.3 115.8h.6l.6 .7-.6 .6h-.6z"/>
<path d="M92.1 108.8h15.2v50.8h-15.2zM127 113.3h.6l.7 .6-.7 .6h-.6zM127 115.8h.6l.7 .7-.7 .6h-.6zM130.8 108.8h15.2v50.8h-15.2zM177.8 112h.6l.7 .6-.7 .7h-.6zM177.8 114.5h.6l.7 .7-.7 .6h-.6zM177.8 117.1h.6l.7 .6-.7 .7h-.6zM184.1 110.1h15.3v22.9h-15.3zM238.4 101.8v3.9M238.4 114.5v3.9M238.9 101.5v1M238.9 103.2v1.1"/>
<path d="M238.9 105v1M238.9 114.2v1M238.9 115.9v1.1M238.9 117.7v1M241.3 110.7h.6v1.3h-.6l-.6-.6zM49.8 122.2h2v5h-2zM51.4 135.5h.7l.6 .6-.6 .7h-.7zM86.6 122.8h2v5.1h-2zM88.3 136.1h.6l.6 .7-.6 .6h-.6zM125.3 122.8h2.1v5.1h-2.1zM127 136.1h.6l.7 .7-.7 .6h-.6zM238.4 126.6v3.8"/>
<path d="M238.4 139.3v3.8M238.9 126.2v1M238.9 128v1M238.9 129.8v1M238.9 138.9v1M241.3 135.5h.6v1.3h-.6l-.6-.7zM241.3 122.8h.6v1.3h-.6l-.6-.7zM238.4 152v3.8M238.9 140.7v1M238.9 142.5v1M238.9 151.6v1M238.9 153.4v1"/>
<path d="M238.9 155.2v1M241.3 148.2h.6v1.3h-.6l-.6-.7z"/>
<circle cx="239.8" cy="90.4" r="2.79"/>
<circle cx="239.8" cy="116.5" r="2.79"/>
<circle cx="239.8" cy="103.8" r="2.79"/>
<circle cx="239.8" cy="128.5" r="2.79"/>
<circle cx="239.8" cy="141.2" r="2.79"/>
<circle cx="239.8" cy="153.9" r="2.79"/>
</g>
<g fill="#000" stroke="#000" stroke-width=".25">
<path d="M206.4 108.5h2.5v.5h-2.5zM40 130h2.5v.6h-2.5zM49.5 130h2.6v.6h-2.6zM86.4 130.7h2.5v.5h-2.5zM125.1 130.7h2.5v.5h-2.5zM177.8 138.9h2.5v.5h-2.5zM190.5 139.6h2.5v.5h-2.5zM47 153.5h2.5v.5h-2.5zM83.8 154.2h2.6v.5h-2.6zM122.6 154.2h2.5v.5h-2.5zM61.6 163.1h2.5v.5h-2.5zM98.4 163.7h2.6v.5h-2.6z"/>
<path d="M137.2 163.7h2.5v.5h-2.5z"/>
<circle cx="179.1" cy="130.4" r=".51"/>
</g>
<g fill="#000" stroke="#000" stroke-width=".18">
<path d="M239.4 90l1 .4-1 .4zM239.4 116.1l1 .4-1 .3zM239.4 103.4l1 .4-1 .3zM239.4 128.1l1 .4-1 .4zM239.4 153.5l1 .4-1 .4zM239.4 140.8l1 .4-1 .4z"/>
<circle cx="240.7" cy="88.6" r=".25"/>
<circle cx="240.7" cy="92.2" r=".25"/>
<circle cx="240.7" cy="105.5" r=".25"/>
<circle cx="240.7" cy="102" r=".25"/>
<circle cx="240.7" cy="114.7" r=".25"/>
<circle cx="240.7" cy="118.2" r=".25"/>
<circle cx="240.7" cy="130.3" r=".25"/>
<circle cx="240.7" cy="139.4" r=".25"/>
<circle cx="240.7" cy="126.7" r=".25"/>
<circle cx="240.7" cy="143" r=".25"/>
<circle cx="240.7" cy="155.7" r=".25"/>
<circle cx="240.7" cy="152.1" r=".25"/>
</g>
<path d="M205.6 103.9h4.1M205.6 102.4h4.1M46.2 149h4.1M46.2 147.4h4.1M83.1 149.6h4M83.1 148.1h4M121.8 149.6h4.1M121.8 148.1h4.1" fill="none" stroke="#000" stroke-width=".51"/>
<path d="M224.6 189.6l-.4 .1-.1 .2M226.2 189.7l-.6-.1-.4 .3v.6l.2 .3 .2 .1 .6-.1M226.2 188.9v2M228.6 188.9a1.06 1.06 0 0 1 1.2 .6 1.06 1.06 0 0 1-.4 1.3l-.8 .1zM230.6 189.1l.2-.2h.5l.3 .2 .1 .4-.1 .3-1.1 1.1h1.2" fill="none" stroke="#000" stroke-width=".41"/>
<use href="#words"/>
</svg>
